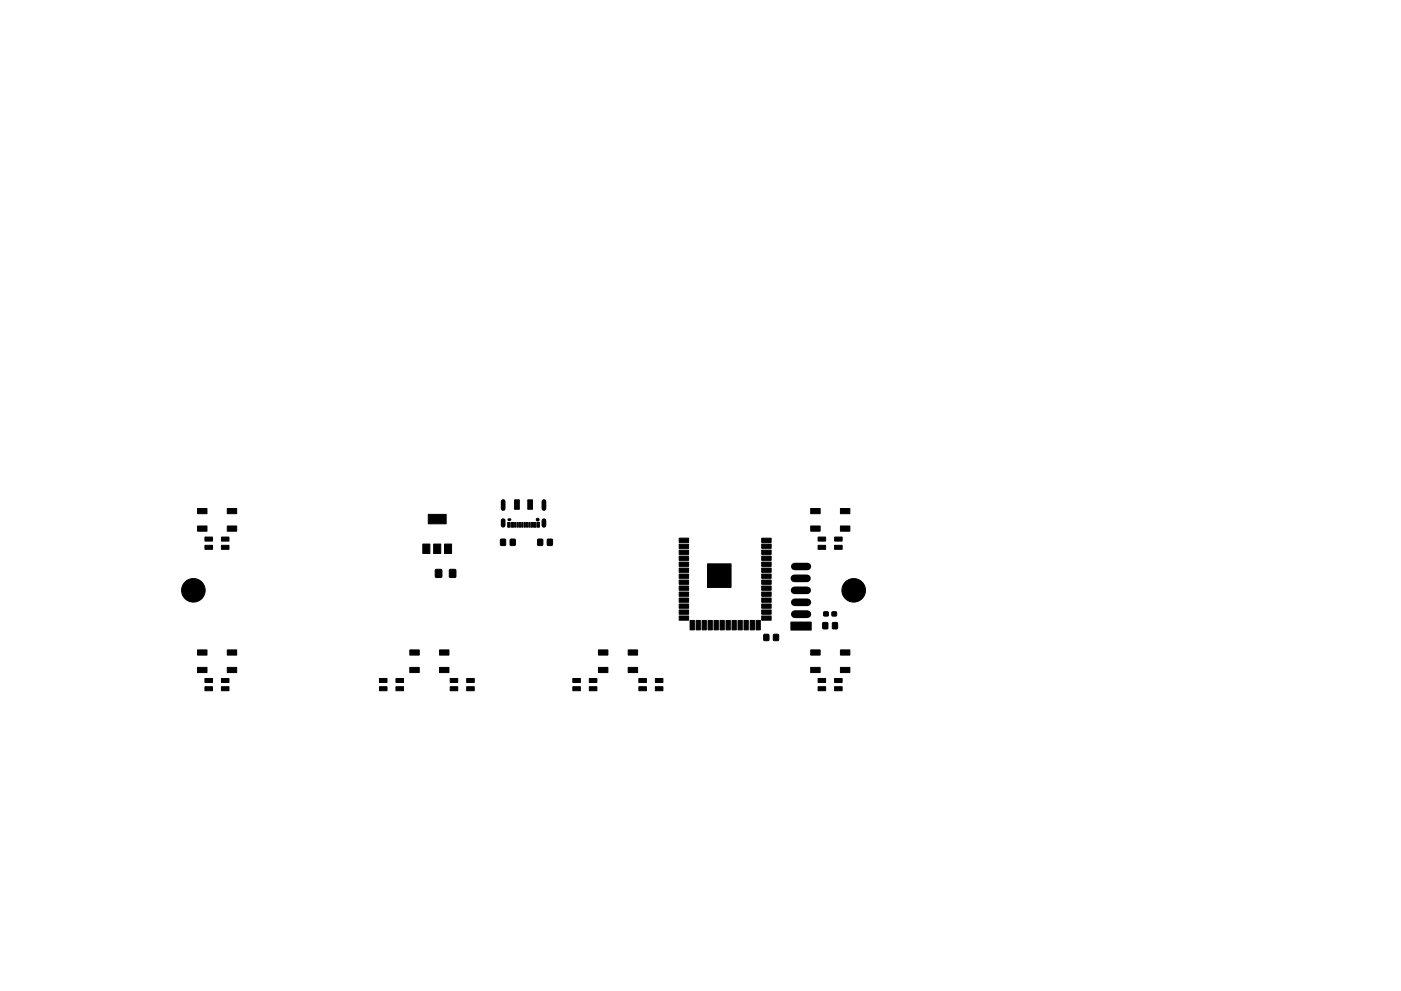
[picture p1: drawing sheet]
<svg xmlns="http://www.w3.org/2000/svg" width="297mm" height="210mm" viewBox="0 0 297 210" stroke-linecap="round" stroke-linejoin="round" font-family="sans-serif">
<g fill="#000" stroke="#000" stroke-width=".21">
<path d="M41.9 107.9h2v1.1h-2zM41.9 111.6h2v1.1h-2zM43.5 113.9h1.5v.9h-1.5zM43.5 115.7h1.5v.8h-1.5zM48.2 107.9h2v1.1h-2zM48.2 111.6h2v1.1h-2zM47 115.7h1.6v.8h-1.6zM47 113.9h1.6v.9h-1.6zM89.6 115.4h1.5v2h-1.5zM91.9 115.4h1.5v2h-1.5zM90.8 109.1h3.8v2h-3.8zM94.2 115.4h1.5v2h-1.5z"/>
<path d="M106.2 114.4h1v1.3h-1zM107.6 110.8h.6v1h-.6zM108.4 110.8h.5v1h-.5zM108.2 114.4h1v1.3h-1zM109.1 110.8h.3v1h-.3zM109.6 110.8h.3v1h-.3zM109.1 106h1v2h-1zM110.1 110.8h.3v1h-.3zM110.6 110.8h.3v1h-.3zM111.1 110.8h.3v1h-.3zM111.6 110.8h.3v1h-.3zM112.1 110.8h.3v1h-.3z"/>
<path d="M112.6 110.8h.3v1h-.3zM111.9 106h1v2h-1zM113.1 110.8h.5v1h-.5zM114 114.4h1v1.3h-1zM113.8 110.8h.6v1h-.6zM116.1 114.4h1v1.3h-1zM144 114.2h2v.9h-2zM144 115.4h2v.9h-2zM144 116.7h2v.9h-2zM144 118h2v.9h-2zM161.5 118h2v.9h-2zM161.5 116.7h2v.9h-2z"/>
<path d="M161.5 115.4h2v.9h-2zM161.5 114.2h2v.9h-2zM171.9 107.9h2v1.1h-2zM171.9 111.6h2v1.1h-2zM173.4 113.9h1.6v.9h-1.6zM173.4 115.7h1.6v.8h-1.6zM178.2 107.9h2v1.1h-2zM178.2 111.6h2v1.1h-2zM177 115.7h1.6v.8h-1.6zM177 113.9h1.6v.9h-1.6zM41.9 137.9h2v1.1h-2zM48.2 137.9h2v1.1h-2z"/>
<path d="M86.9 137.9h2v1.1h-2zM92.3 120.9h1.3v1.6h-1.3zM93.2 137.9h2v1.1h-2zM95.3 120.9h1.3v1.6h-1.3zM126.9 137.9h2v1.1h-2zM133.2 137.9h2v1.1h-2zM144 119.3h2v.9h-2zM144 120.5h2v.9h-2zM144 121.8h2v.9h-2zM144 123.1h2v.9h-2zM144 124.3h2v.9h-2zM144 125.6h2v.9h-2z"/>
<path d="M144 126.9h2v.9h-2zM144 128.1h2v.9h-2zM144 129.4h2v.9h-2zM144 130.7h2v.9h-2zM146.3 131.6h.9v2h-.9zM147.6 131.6h.9v2h-.9zM148.9 131.6h.9v2h-.9zM150 119.6h5v5h-5zM150.1 131.6h.9v2h-.9zM151.4 131.6h.9v2h-.9zM152.7 131.6h.9v2h-.9zM153.9 131.6h.9v2h-.9z"/>
<path d="M155.2 131.6h.9v2h-.9zM156.5 131.6h.9v2h-.9zM157.7 131.6h.9v2h-.9zM159 131.6h.9v2h-.9zM160.3 131.6h.9v2h-.9zM161.5 130.7h2v.9h-2zM161.5 129.4h2v.9h-2zM161.5 128.1h2v.9h-2zM161.5 126.9h2v.9h-2zM161.5 125.6h2v.9h-2zM161.5 124.3h2v.9h-2zM161.5 123.1h2v.9h-2z"/>
<path d="M161.5 121.8h2v.9h-2zM161.5 120.5h2v.9h-2zM161.5 119.3h2v.9h-2zM162 134.6h1v1.3h-1zM164 134.6h1v1.3h-1zM171.9 137.9h2v1.1h-2zM167.7 132h4.3v1.7h-4.3zM174.7 129.8h.9v.9h-.9zM174.5 132.1h1v1.3h-1zM176.4 129.8h.9v.9h-.9zM176.5 132.1h1v1.3h-1zM178.2 137.9h2v1.1h-2z"/>
<path d="M41.9 141.6h2v1.1h-2zM43.5 143.9h1.5v.9h-1.5zM43.5 145.7h1.5v.8h-1.5zM48.2 141.6h2v1.1h-2zM47 145.7h1.6v.8h-1.6zM47 143.9h1.6v.9h-1.6zM80.4 145.7h1.6v.8h-1.6zM80.4 143.9h1.6v.9h-1.6zM84 143.9h1.5v.9h-1.5zM84 145.7h1.5v.8h-1.5zM86.9 141.6h2v1.1h-2zM93.2 141.6h2v1.1h-2z"/>
<path d="M95.4 143.9h1.7v.9h-1.7zM95.4 145.7h1.7v.8h-1.7zM99 145.7h1.5v.8h-1.5zM99 143.9h1.5v.9h-1.5zM121.5 143.9h1.6v.9h-1.6zM121.5 145.7h1.6v.8h-1.6zM124.9 145.7h1.6v.8h-1.6zM124.9 143.9h1.6v.9h-1.6zM126.9 141.6h2v1.1h-2zM133.2 141.6h2v1.1h-2zM135.5 143.9h1.6v.9h-1.6zM135.5 145.7h1.6v.8h-1.6z"/>
<path d="M138.9 145.7h1.6v.8h-1.6zM138.9 143.9h1.6v.9h-1.6zM171.9 141.6h2v1.1h-2zM173.4 143.9h1.6v.9h-1.6zM173.4 145.7h1.6v.8h-1.6zM178.2 141.6h2v1.1h-2zM177 145.7h1.6v.8h-1.6zM177 143.9h1.6v.9h-1.6z"/>
<circle cx="114" cy="110.2" r=".3"/>
<circle cx="41" cy="125.2" r="2.5"/>
<circle cx="181" cy="125.2" r="2.5"/>
</g>
<path d="M168.5 130.3h2.7" fill="none" stroke="#000" stroke-width="1.7"/>
<path d="M168.4 122.7h2.7M168.5 125.2h2.6M168.5 120.2h2.7M168.5 127.8h2.7" fill="none" stroke="#000" stroke-width="1.6"/>
<path d="M106.7 106.4v1.5M106.7 110.4v1M115.3 106.4v1.5M115.3 110.5v1" fill="none" stroke="#000" stroke-width="1"/>
<path d="M107.9 110.2h.2" fill="none" stroke="#000" stroke-width=".6"/>
</svg>
